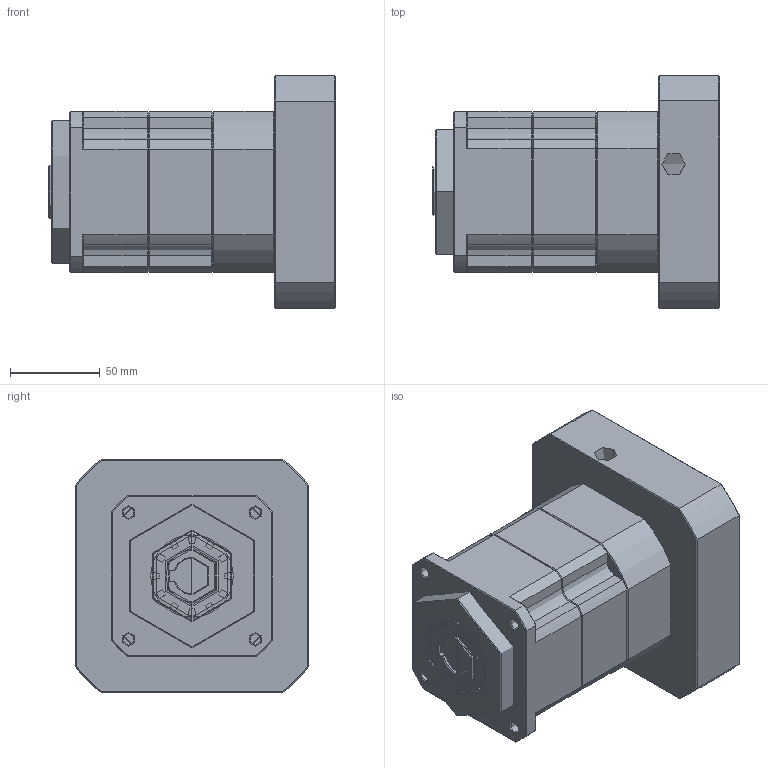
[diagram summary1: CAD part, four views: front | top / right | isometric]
STEP (ISO 10303-21) file: header records copied from the file, then geometry measured from it (millimetres).
FILE_DESCRIPTION (( 'STEP AP214' ), '1' );
FILE_NAME ('ZPB090-K20-L2-P1-19-110-145-M8.step', '2024-06-07T18:26:03', ( 'Windows 蚚誧' ), ( 'Organization' ), 'SwSTEP 2.0', 'SolidWorks 2016', '' );
FILE_SCHEMA (( 'AUTOMOTIVE_DESIGN' ));
Length unit declared in the file: millimetre
Products named in the file (1): ZPB090-K20-L2-P1-19-110-145-M8
Bounding box: 160 x 130 x 130 mm (x, y, z)
Topology: 0 solids, 36 shells, 1862 faces, 4905 edges, 3111 vertices
Faces by surface type: plane 962, bspline 384, cone 285, cylinder 231
Entity records: 88179 total; most frequent: CARTESIAN_POINT 40492, ORIENTED_EDGE 9790, DIRECTION 7592, EDGE_CURVE 4906, LINE 3248, VECTOR 3248, VERTEX_POINT 3111, AXIS2_PLACEMENT_3D 2172
One B-rep face of a CAD part: STEP entity #32766.
In plain terms, the planar face has unit normal (-1, 0, 0).
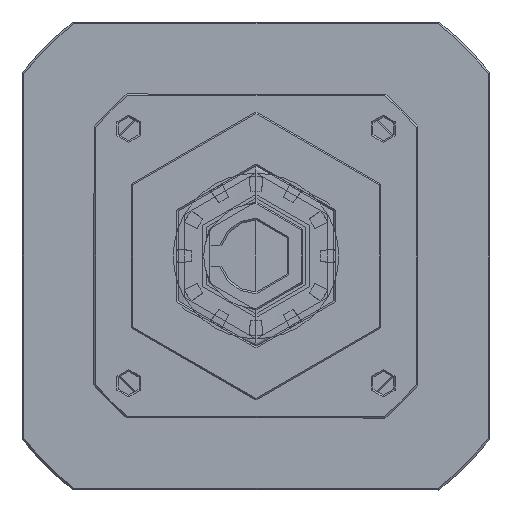
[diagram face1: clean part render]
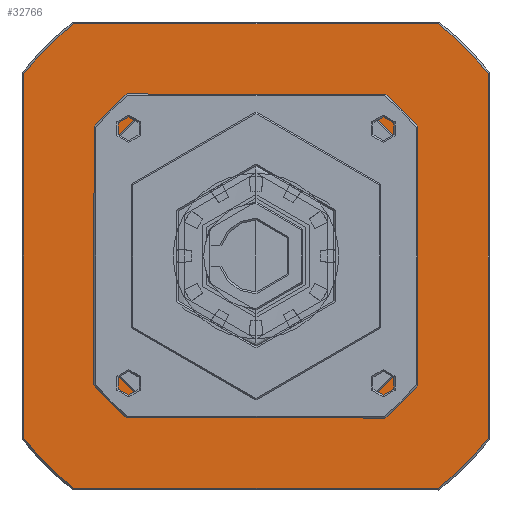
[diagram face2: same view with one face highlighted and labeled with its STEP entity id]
Its self-contained STEP definition (entity closure, numbers rounded to 3 decimals):
#1156 = CIRCLE ( 'NONE', #89723, 82. ) ;
#1175 = CARTESIAN_POINT ( 'NONE',  ( 124.5, 0., -64.5 ) ) ;
#2931 = DIRECTION ( 'NONE',  ( 0., 0., -1. ) ) ;
#4500 = CARTESIAN_POINT ( 'NONE',  ( 124.5, 0., 0. ) ) ;
#5650 = EDGE_CURVE ( 'NONE', #9688, #49186, #15663, .T. ) ;
#6922 = CARTESIAN_POINT ( 'NONE',  ( 124.5, 64.5, 50.633 ) ) ;
#7183 = EDGE_LOOP ( 'NONE', ( #20565, #10151, #17199, #7984, #78832, #43093, #8868, #74502 ) ) ;
#7506 = CARTESIAN_POINT ( 'NONE',  ( 124.5, -23.875, -44.5 ) ) ;
#7984 = ORIENTED_EDGE ( 'NONE', *, *, #31586, .F. ) ;
#8051 = ORIENTED_EDGE ( 'NONE', *, *, #31868, .T. ) ;
#8868 = ORIENTED_EDGE ( 'NONE', *, *, #50130, .F. ) ;
#9288 = CARTESIAN_POINT ( 'NONE',  ( 124.5, -64.5, 64.5 ) ) ;
#9688 = VERTEX_POINT ( 'NONE', #7506 ) ;
#10151 = ORIENTED_EDGE ( 'NONE', *, *, #16205, .F. ) ;
#10819 = DIRECTION ( 'NONE',  ( 0., 0., 1. ) ) ;
#11721 = LINE ( 'NONE', #56350, #78767 ) ;
#12575 = CARTESIAN_POINT ( 'NONE',  ( 124.5, 0., 0. ) ) ;
#13584 = FACE_BOUND ( 'NONE', #7183, .T. ) ;
#13869 = ORIENTED_EDGE ( 'NONE', *, *, #84420, .T. ) ;
#14254 = AXIS2_PLACEMENT_3D ( 'NONE', #18654, #18362, #10819 ) ;
#14894 = ORIENTED_EDGE ( 'NONE', *, *, #14968, .T. ) ;
#14968 = EDGE_CURVE ( 'NONE', #83996, #45438, #81280, .T. ) ;
#15256 = CARTESIAN_POINT ( 'NONE',  ( 124.5, -44.5, -23.875 ) ) ;
#15663 = CIRCLE ( 'NONE', #26977, 50.5 ) ;
#16205 = EDGE_CURVE ( 'NONE', #71788, #47241, #27933, .T. ) ;
#16246 = VERTEX_POINT ( 'NONE', #65543 ) ;
#16908 = AXIS2_PLACEMENT_3D ( 'NONE', #9288, #50094, #2931 ) ;
#17087 = ORIENTED_EDGE ( 'NONE', *, *, #28430, .T. ) ;
#17154 = CARTESIAN_POINT ( 'NONE',  ( 124.5, 0., 44.5 ) ) ;
#17199 = ORIENTED_EDGE ( 'NONE', *, *, #78789, .T. ) ;
#17754 = LINE ( 'NONE', #23585, #43642 ) ;
#17907 = CARTESIAN_POINT ( 'NONE',  ( 124.5, -50.633, 64.5 ) ) ;
#18362 = DIRECTION ( 'NONE',  ( 1., 0., 0. ) ) ;
#18381 = DIRECTION ( 'NONE',  ( 0., 0., -1. ) ) ;
#18654 = CARTESIAN_POINT ( 'NONE',  ( 124.5, 0., 0. ) ) ;
#18931 = CIRCLE ( 'NONE', #80275, 82. ) ;
#19068 = CARTESIAN_POINT ( 'NONE',  ( 124.5, 64.5, -50.633 ) ) ;
#19374 = CARTESIAN_POINT ( 'NONE',  ( 124.5, -64.5, 50.633 ) ) ;
#19589 = VERTEX_POINT ( 'NONE', #57575 ) ;
#19781 = DIRECTION ( 'NONE',  ( 0., 0., -1. ) ) ;
#20051 = VECTOR ( 'NONE', #26663, 1000. ) ;
#20067 = DIRECTION ( 'NONE',  ( -1., 0., 0. ) ) ;
#20138 = DIRECTION ( 'NONE',  ( -1., 0., 0. ) ) ;
#20238 = VERTEX_POINT ( 'NONE', #27807 ) ;
#20565 = ORIENTED_EDGE ( 'NONE', *, *, #37297, .T. ) ;
#21401 = CIRCLE ( 'NONE', #14254, 50.5 ) ;
#21569 = VECTOR ( 'NONE', #31853, 1000. ) ;
#21957 = CARTESIAN_POINT ( 'NONE',  ( 124.5, 0., 0. ) ) ;
#23473 = CIRCLE ( 'NONE', #43763, 82. ) ;
#23585 = CARTESIAN_POINT ( 'NONE',  ( 124.5, -64.5, 0. ) ) ;
#25016 = DIRECTION ( 'NONE',  ( 0., 0., 1. ) ) ;
#25229 = EDGE_CURVE ( 'NONE', #16246, #9688, #37761, .T. ) ;
#26492 = DIRECTION ( 'NONE',  ( -1., 0., 0. ) ) ;
#26663 = DIRECTION ( 'NONE',  ( 0., 0., -1. ) ) ;
#26762 = VECTOR ( 'NONE', #85300, 1000. ) ;
#26977 = AXIS2_PLACEMENT_3D ( 'NONE', #81708, #75333, #82887 ) ;
#27807 = CARTESIAN_POINT ( 'NONE',  ( 124.5, -64.5, -50.633 ) ) ;
#27933 = LINE ( 'NONE', #17154, #30094 ) ;
#28310 = DIRECTION ( 'NONE',  ( 1., 0., 0. ) ) ;
#28368 = DIRECTION ( 'NONE',  ( -1., 0., 0. ) ) ;
#28430 = EDGE_CURVE ( 'NONE', #19589, #35363, #1156, .T. ) ;
#29958 = VECTOR ( 'NONE', #80775, 1000. ) ;
#30094 = VECTOR ( 'NONE', #52516, 1000. ) ;
#30707 = CARTESIAN_POINT ( 'NONE',  ( 124.5, 44.5, 23.875 ) ) ;
#30833 = CIRCLE ( 'NONE', #79823, 50.5 ) ;
#31586 = EDGE_CURVE ( 'NONE', #49186, #65424, #54862, .T. ) ;
#31805 = VERTEX_POINT ( 'NONE', #19068 ) ;
#31853 = DIRECTION ( 'NONE',  ( 0., -1., 0. ) ) ;
#31868 = EDGE_CURVE ( 'NONE', #77203, #19589, #32165, .T. ) ;
#32165 = LINE ( 'NONE', #66888, #29958 ) ;
#32236 = VERTEX_POINT ( 'NONE', #58043 ) ;
#32766 = ADVANCED_FACE ( 'NONE', ( #13584, #80655 ), #50691, .F. ) ;
#33963 = EDGE_CURVE ( 'NONE', #20238, #46336, #17754, .T. ) ;
#35363 = VERTEX_POINT ( 'NONE', #6922 ) ;
#37297 = EDGE_CURVE ( 'NONE', #85334, #47241, #21401, .T. ) ;
#37761 = LINE ( 'NONE', #66919, #21569 ) ;
#41337 = CARTESIAN_POINT ( 'NONE',  ( 124.5, -44.5, 23.875 ) ) ;
#41461 = ORIENTED_EDGE ( 'NONE', *, *, #48617, .T. ) ;
#43093 = ORIENTED_EDGE ( 'NONE', *, *, #25229, .F. ) ;
#43642 = VECTOR ( 'NONE', #44395, 1000. ) ;
#43763 = AXIS2_PLACEMENT_3D ( 'NONE', #69200, #28368, #69506 ) ;
#44395 = DIRECTION ( 'NONE',  ( 0., 0., 1. ) ) ;
#45438 = VERTEX_POINT ( 'NONE', #81105 ) ;
#46336 = VERTEX_POINT ( 'NONE', #19374 ) ;
#47241 = VERTEX_POINT ( 'NONE', #69773 ) ;
#47564 = CARTESIAN_POINT ( 'NONE',  ( 124.5, 0., 0. ) ) ;
#47921 = AXIS2_PLACEMENT_3D ( 'NONE', #21957, #28310, #49163 ) ;
#48617 = EDGE_CURVE ( 'NONE', #46336, #77203, #23473, .T. ) ;
#49163 = DIRECTION ( 'NONE',  ( 0., 0., 1. ) ) ;
#49186 = VERTEX_POINT ( 'NONE', #15256 ) ;
#49372 = AXIS2_PLACEMENT_3D ( 'NONE', #47564, #20067, #61525 ) ;
#50094 = DIRECTION ( 'NONE',  ( 1., 0., 0. ) ) ;
#50130 = EDGE_CURVE ( 'NONE', #32236, #16246, #30833, .T. ) ;
#50566 = CARTESIAN_POINT ( 'NONE',  ( 124.5, -44.5, 0. ) ) ;
#50691 = PLANE ( 'NONE',  #16908 ) ;
#52048 = VECTOR ( 'NONE', #57984, 1000. ) ;
#52516 = DIRECTION ( 'NONE',  ( 0., 1., 0. ) ) ;
#54862 = LINE ( 'NONE', #50566, #26762 ) ;
#56350 = CARTESIAN_POINT ( 'NONE',  ( 124.5, 44.5, 0. ) ) ;
#57194 = ORIENTED_EDGE ( 'NONE', *, *, #85423, .T. ) ;
#57575 = CARTESIAN_POINT ( 'NONE',  ( 124.5, 50.633, 64.5 ) ) ;
#57984 = DIRECTION ( 'NONE',  ( 0., -1., 0. ) ) ;
#58043 = CARTESIAN_POINT ( 'NONE',  ( 124.5, 44.5, -23.875 ) ) ;
#61160 = CARTESIAN_POINT ( 'NONE',  ( 124.5, 64.5, 0. ) ) ;
#61525 = DIRECTION ( 'NONE',  ( 0., 0., -1. ) ) ;
#64543 = EDGE_CURVE ( 'NONE', #85334, #32236, #11721, .T. ) ;
#65424 = VERTEX_POINT ( 'NONE', #41337 ) ;
#65543 = CARTESIAN_POINT ( 'NONE',  ( 124.5, 23.875, -44.5 ) ) ;
#66888 = CARTESIAN_POINT ( 'NONE',  ( 124.5, 0., 64.5 ) ) ;
#66919 = CARTESIAN_POINT ( 'NONE',  ( 124.5, 0., -44.5 ) ) ;
#67085 = DIRECTION ( 'NONE',  ( -1., 0., 0. ) ) ;
#68398 = CIRCLE ( 'NONE', #47921, 50.5 ) ;
#69200 = CARTESIAN_POINT ( 'NONE',  ( 124.5, 0., 0. ) ) ;
#69452 = CARTESIAN_POINT ( 'NONE',  ( 124.5, -23.875, 44.5 ) ) ;
#69506 = DIRECTION ( 'NONE',  ( 0., 0., -1. ) ) ;
#69773 = CARTESIAN_POINT ( 'NONE',  ( 124.5, 23.875, 44.5 ) ) ;
#69977 = DIRECTION ( 'NONE',  ( 0., 0., -1. ) ) ;
#70800 = ORIENTED_EDGE ( 'NONE', *, *, #76868, .T. ) ;
#71788 = VERTEX_POINT ( 'NONE', #69452 ) ;
#72126 = CIRCLE ( 'NONE', #49372, 82. ) ;
#74502 = ORIENTED_EDGE ( 'NONE', *, *, #64543, .F. ) ;
#75333 = DIRECTION ( 'NONE',  ( -1., 0., 0. ) ) ;
#75473 = CARTESIAN_POINT ( 'NONE',  ( 124.5, 0., 0. ) ) ;
#76821 = LINE ( 'NONE', #61160, #20051 ) ;
#76868 = EDGE_CURVE ( 'NONE', #45438, #20238, #18931, .T. ) ;
#77203 = VERTEX_POINT ( 'NONE', #17907 ) ;
#78767 = VECTOR ( 'NONE', #69977, 1000. ) ;
#78789 = EDGE_CURVE ( 'NONE', #71788, #65424, #68398, .T. ) ;
#78832 = ORIENTED_EDGE ( 'NONE', *, *, #5650, .F. ) ;
#79823 = AXIS2_PLACEMENT_3D ( 'NONE', #75473, #20138, #25016 ) ;
#80275 = AXIS2_PLACEMENT_3D ( 'NONE', #12575, #26492, #19781 ) ;
#80655 = FACE_OUTER_BOUND ( 'NONE', #81319, .T. ) ;
#80775 = DIRECTION ( 'NONE',  ( 0., 1., 0. ) ) ;
#81105 = CARTESIAN_POINT ( 'NONE',  ( 124.5, -50.633, -64.5 ) ) ;
#81280 = LINE ( 'NONE', #1175, #52048 ) ;
#81319 = EDGE_LOOP ( 'NONE', ( #17087, #13869, #57194, #14894, #70800, #83462, #41461, #8051 ) ) ;
#81708 = CARTESIAN_POINT ( 'NONE',  ( 124.5, 0., 0. ) ) ;
#82887 = DIRECTION ( 'NONE',  ( 0., 0., 1. ) ) ;
#83462 = ORIENTED_EDGE ( 'NONE', *, *, #33963, .T. ) ;
#83996 = VERTEX_POINT ( 'NONE', #86293 ) ;
#84420 = EDGE_CURVE ( 'NONE', #35363, #31805, #76821, .T. ) ;
#85300 = DIRECTION ( 'NONE',  ( 0., 0., 1. ) ) ;
#85334 = VERTEX_POINT ( 'NONE', #30707 ) ;
#85423 = EDGE_CURVE ( 'NONE', #31805, #83996, #72126, .T. ) ;
#86293 = CARTESIAN_POINT ( 'NONE',  ( 124.5, 50.633, -64.5 ) ) ;
#89723 = AXIS2_PLACEMENT_3D ( 'NONE', #4500, #67085, #18381 ) ;
